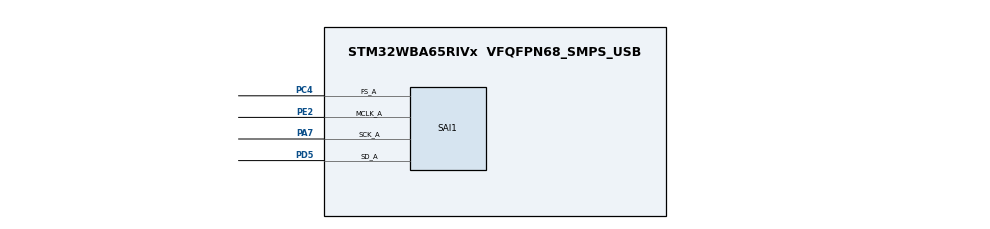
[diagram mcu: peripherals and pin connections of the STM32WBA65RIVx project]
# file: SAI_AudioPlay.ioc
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CORTEX_M33_NS.userName=CORTEX_M33
GPDMA1.LINKEDLISTMODE_GPDMACH7=DMA_LINKEDLIST_CIRCULAR
GPDMA1.PRIORITY_LL_GPDMACH7=DMA_HIGH_PRIORITY
Linkedlist.MDMA_Channel0.GP_SW.0.BlkHWRequest=DMA_BREQ_SINGLE_BURST
Linkedlist.MDMA_Channel0.GP_SW.0.DataHandling=NONE
Linkedlist.MDMA_Channel0.GP_SW.0.DataSize=0
Linkedlist.MDMA_Channel0.GP_SW.0.DestBurstLength=1
Linkedlist.MDMA_Channel0.GP_SW.0.DestDataWidth=DMA_DEST_DATAWIDTH_HALFWORD
Linkedlist.MDMA_Channel0.GP_SW.0.DestInc=DMA_DINC_FIXED
Linkedlist.MDMA_Channel0.GP_SW.0.Direction=DMA_MEMORY_TO_PERIPH
Linkedlist.MDMA_Channel0.GP_SW.0.DstAddress=0
Linkedlist.MDMA_Channel0.GP_SW.0.Instance=MDMA_Channel0
Linkedlist.MDMA_Channel0.GP_SW.0.LL_MASTERDMA=GPDMA1
Linkedlist.MDMA_Channel0.GP_SW.0.LL_NAME=SAIQueue
Linkedlist.MDMA_Channel0.GP_SW.0.LL_TYPE=LINEAR
Linkedlist.MDMA_Channel0.GP_SW.0.NODE_NAME=NodeTx
Linkedlist.MDMA_Channel0.GP_SW.0.Requestforcodegen=GPDMA1_REQUEST_SAI1_A
Linkedlist.MDMA_Channel0.GP_SW.0.SrcAddress=0
Linkedlist.MDMA_Channel0.GP_SW.0.SrcBurstLength=1
Linkedlist.MDMA_Channel0.GP_SW.0.SrcDataWidth=DMA_SRC_DATAWIDTH_HALFWORD
Linkedlist.MDMA_Channel0.GP_SW.0.SrcInc=DMA_SINC_INCREMENTED
Linkedlist.MDMA_Channel0.GP_SW.0.TransferAllocatedPortSrc=DMA_SRC_ALLOCATED_PORT0
Linkedlist.MDMA_Channel0.GP_SW.0.TransferEventMode=DMA_TCEM_BLOCK_TRANSFER
Linkedlist.MDMA_Channel0.GP_SW.0.TriggerPolarity=DMA_TRIG_POLARITY_MASKED
Linkedlist.MDMA_Channel0.Request0=GP_SW
Linkedlist.MDMA_Channel0.RequestsNb=1
Linkedlist.RequestSet0=MDMA_Channel0
Linkedlist.RequestSetsNb=1
Mcu.Family=STM32WBA
Mcu.Name=STM32WBA65RIVx
Mcu.Package=VFQFPN68_SMPS_USB
NVIC.GPDMA1_Channel7_IRQn=true\:0\:0\:false\:false\:true\:true\:true\:true
NVIC.PriorityGroup=NVIC_PRIORITYGROUP_4
OSC_IN.Mode=HSE-External-Oscillator
OSC_IN.PinAttribute=CortexM33
OSC_IN.Signal=RCC_OSC_IN
OSC_OUT.Mode=HSE-External-Oscillator
OSC_OUT.PinAttribute=CortexM33
OSC_OUT.Signal=RCC_OSC_OUT
PA7.Mode=SAI_A_MasterWithClock
PA7.PinAttribute=CortexM33
PA7.Signal=SAI1_SCK_A
PC4.Mode=SAI_A_MasterWithClock
PC4.Signal=SAI1_FS_A
PD5.Mode=SAI_A_MasterWithClock
PD5.Signal=SAI1_SD_A
PE2.Mode=SAI_A_MasterWithClock
PE2.Signal=SAI1_MCLK_A
ProjectManager.HeapSize=0x200
ProjectManager.StackSize=0x400
ProjectManager.TargetToolchain=EWARM V9.20
RCC.ADCFreq_Value=100000000
RCC.AHB5CLKDivider=DIV4
RCC.AHBFreq_Value=100000000
RCC.APB1Freq_Value=100000000
RCC.APB1TimFreq_Value=100000000
RCC.APB2Freq_Value=100000000
RCC.APB2TimFreq_Value=100000000
RCC.CortexFreq_Value=12500000
RCC.HCLKFreq_Value=100000000
RCC.HSE_VALUE=32000000
RCC.HSI_VALUE=16000000
RCC.LSE_VALUE=32768
RCC.LSI1_VALUE=32000
RCC.LSI2_VALUE=32000
RCC.PLLFRACN=4096
RCC.PLLM=2
RCC.PLLN=12
RCC.PLLSourceVirtual=RCC_PLLSOURCE_HSE
RCC.SYSCLKFreq_VALUE=100000000
RCC.SYSCLKSourceVirtual=RCC_SYSCLKSOURCE_PLLCLK
RCC.VCOOutputFreq_Value=200000000
SAI1.ActiveFrameLength-SAI_A_MasterWithClock=16
SAI1.AudioFrequency-SAI_A_MasterWithClock=SAI_AUDIO_FREQUENCY_22K
SAI1.DataSize-SAI_A_MasterWithClock=SAI_DATASIZE_16
SAI1.ErrorAudioFreq-SAI_A_MasterWithClock=41.72 %
SAI1.FIFOThreshold-SAI_A_MasterWithClock=SAI_FIFOTHRESHOLD_1QF
SAI1.FSDefinition-SAI_A_MasterWithClock=SAI_FS_CHANNEL_IDENTIFICATION
SAI1.FSOffset-SAI_A_MasterWithClock=SAI_FS_BEFOREFIRSTBIT
SAI1.FrameLength-SAI_A_MasterWithClock=32
SAI1.Instance-SAI_A_MasterWithClock=SAI$Index_Block_A
SAI1.MckOutput=SAI_MCK_OUTPUT_ENABLE
SAI1.RealAudioFreq-SAI_A_MasterWithClock=31.25 KHz
SAI1.SlotActive-SAI_A_MasterWithClock=0x00000003
SAI1.SlotNumber-SAI_A_MasterWithClock=2
SAI1.VirtualMode-SAI_A_MasterWithClock=VM_MASTER
SAI1.VirtualSlotActive-SAI_A_MasterWithClock=SAI_SLOT_USERSETTING
SAI1.VirtualSlotActive0-SAI_A_MasterWithClock=true
SAI1.VirtualSlotActive1-SAI_A_MasterWithClock=true
VP_CORTEX_M33_NS_VS_Hclk.Mode=Hclk_Mode
VP_GPDMA1_VS_GPDMACH7.Mode=LINKEDLIST_GPDMACH7
VP_ICACHE_VS_ICACHE.Mode=DirectMappedCache
VP_MEMORYMAP_VS_MEMORYMAP.Mode=CurAppReg
VP_PWR_VS_SECSignals.Mode=Security/Privilege
board=custom

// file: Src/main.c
/* USER CODE BEGIN Header */
/**
  ******************************************************************************
  * @file           : main.c
  * @brief          : Main program body
  ******************************************************************************
  * @attention
  *
  * Copyright (c) 2024 STMicroelectronics.
  * All rights reserved.
  *
  * This software is licensed under terms that can be found in the LICENSE file
  * in the root directory of this software component.
  * If no LICENSE file comes with this software, it is provided AS-IS.
  *
  ******************************************************************************
  */
/* USER CODE END Header */
#include "main.h"

/* USER CODE BEGIN Includes */
#include "linked_list.h"
/* USER CODE END Includes */

DMA_HandleTypeDef handle_GPDMA1_Channel7;

SAI_HandleTypeDef hsai_BlockA1;

/* USER CODE BEGIN PV */
static AUDIO_Drv_t *AudioDrv = NULL;
void *AudioCompObj;

/* Buffer location should aligned to cache line size (32 bytes) */
uint16_t PlayBuff[PLAY_BUFF_SIZE];

__IO int16_t UpdatePointer = -1;
WM8904_Init_t codec_init;
 extern DMA_QListTypeDef SAIQueue;
 extern DMA_NodeTypeDef NodeTx;

/* USER CODE END PV */

void SystemClock_Config(void);
static void MX_GPDMA1_Init(void);
static void MX_GPIO_Init(void);
static void MX_ICACHE_Init(void);
static void MX_SAI1_Init(void);
/* USER CODE BEGIN PFP */
static int32_t WM8904_Probe(void);
/* USER CODE END PFP */

int main(void)
{

  /* USER CODE BEGIN 1 */
  /* STM32WBAxx HAL library initialization:
       - Systick timer is configured by default as source of time base, but user
             can eventually implement his proper time base source (a general purpose
             timer for example or other time source), keeping in mind that Time base
             duration should be kept 1ms since PPP_TIMEOUT_VALUEs are defined and
             handled in milliseconds basis.
       - Set NVIC Group Priority to 4
       - Low Level Initialization
     */
  /* USER CODE END 1 */

  /* MCU Configuration--------------------------------------------------------*/

  /* Reset of all peripherals, Initializes the Flash interface and the Systick. */
  HAL_Init();

  /* USER CODE BEGIN Init */
  uint32_t PlaybackPosition   = PLAY_BUFF_SIZE + PLAY_HEADER;
  /* USER CODE END Init */

  /* Configure the system clock */
  SystemClock_Config();

  /* Initialize all configured peripherals */
  MX_GPDMA1_Init();
  MX_GPIO_Init();
  MX_ICACHE_Init();
  MX_SAI1_Init();
  /* USER CODE BEGIN 2 */
  BSP_LED_Init(LD6);
  BSP_LED_Init(LD5);

  /* Check if the buffer has been loaded in flash */
  if(*((uint64_t *)AUDIO_FILE_ADDRESS) != 0x017EFE2446464952 ) Error_Handler();

    /* Associate the DMA handle */
  __HAL_LINKDMA(&hsai_BlockA1, hdmatx, handle_GPDMA1_Channel7);

   MX_SAIQueue_Config();

  /* Set queue circular mode for sai queue */
  HAL_DMAEx_List_SetCircularMode(&SAIQueue);

  /* Link SAI queue to DMA channel */
  HAL_DMAEx_List_LinkQ(&handle_GPDMA1_Channel7, &SAIQueue);

  WM8904_Probe();

 /* Fill codec_init structure */
 codec_init.InputDevice  = WM8904_IN_NONE;
 codec_init.OutputDevice = WM8904_OUT_HEADPHONE;
 codec_init.Frequency    = AUDIO_FREQUENCY_22K;
 codec_init.Resolution   = WM8904_RESOLUTION_16B; /* Not used */
 codec_init.Volume       = 80;

 /* Initialize the codec internal registers */
 if(AudioDrv->Init(AudioCompObj, &codec_init) < 0)
 {
   Error_Handler();
 }

  /* Initialize the data buffer */
  for(int i=0; i < PLAY_BUFF_SIZE; i+=2)
  {
    PlayBuff[i]=*((__IO uint16_t *)(AUDIO_FILE_ADDRESS + PLAY_HEADER + i));
  }

  /* Start the playback */
  if(0 != AudioDrv->Play(AudioCompObj))
  {
    Error_Handler();
  }

  if(HAL_OK != HAL_SAI_Transmit_DMA(&hsai_BlockA1, (uint8_t *)PlayBuff, PLAY_BUFF_SIZE))
  {
    Error_Handler();
  }

  /* USER CODE END 2 */

  /* Infinite loop */
  while (1)
  {

    /* USER CODE BEGIN 3 */
     BSP_LED_Toggle(LD6);

    /* Wait a callback event */
    while(UpdatePointer==-1);

    int position = UpdatePointer;
    UpdatePointer = -1;

    /* Update the first or the second part of the buffer */
    for(int i = 0; i < PLAY_BUFF_SIZE/2; i++)
    {
      PlayBuff[i+position] = *(uint16_t *)(AUDIO_FILE_ADDRESS + PlaybackPosition);
      PlaybackPosition+=2;
    }

    /* check the end of the file */
    if((PlaybackPosition+PLAY_BUFF_SIZE/2) > AUDIO_FILE_SIZE)
    {
      PlaybackPosition = PLAY_HEADER;
    }

    if(UpdatePointer != -1)
    {
      /* Buffer update time is too long compare to the data transfer time */
      Error_Handler();
    }
  }
  /* USER CODE END 3 */
}

void SystemClock_Config(void)
{
  RCC_OscInitTypeDef RCC_OscInitStruct = {0};
  RCC_ClkInitTypeDef RCC_ClkInitStruct = {0};

  /** Supply configuration update enable
  */
  HAL_PWREx_ConfigSupply(PWR_LDO_SUPPLY);

  /** Configure the main internal regulator output voltage
  */
  if (HAL_PWREx_ControlVoltageScaling(PWR_REGULATOR_VOLTAGE_SCALE1) != HAL_OK)
  {
    Error_Handler();
  }

  /** Initializes the CPU, AHB and APB busses clocks
  */
  RCC_OscInitStruct.OscillatorType = RCC_OSCILLATORTYPE_HSI|RCC_OSCILLATORTYPE_HSE;
  RCC_OscInitStruct.HSEState = RCC_HSE_ON;
  RCC_OscInitStruct.HSEDiv = RCC_HSE_DIV1;
  RCC_OscInitStruct.HSIState = RCC_HSI_ON;
  RCC_OscInitStruct.HSICalibrationValue = RCC_HSICALIBRATION_DEFAULT;
  RCC_OscInitStruct.PLL1.PLLState = RCC_PLL_ON;
  RCC_OscInitStruct.PLL1.PLLSource = RCC_PLLSOURCE_HSE;
  RCC_OscInitStruct.PLL1.PLLM = 2;
  RCC_OscInitStruct.PLL1.PLLN = 12;
  RCC_OscInitStruct.PLL1.PLLP = 2;
  RCC_OscInitStruct.PLL1.PLLQ = 2;
  RCC_OscInitStruct.PLL1.PLLR = 2;
  RCC_OscInitStruct.PLL1.PLLFractional = 4096;
  if (HAL_RCC_OscConfig(&RCC_OscInitStruct) != HAL_OK)
  {
    Error_Handler();
  }

  /** Initializes the CPU, AHB and APB busses clocks
  */
  RCC_ClkInitStruct.ClockType = RCC_CLOCKTYPE_HCLK|RCC_CLOCKTYPE_SYSCLK
                              |RCC_CLOCKTYPE_PCLK1|RCC_CLOCKTYPE_PCLK2
                              |RCC_CLOCKTYPE_PCLK7|RCC_CLOCKTYPE_HCLK5;
  RCC_ClkInitStruct.SYSCLKSource = RCC_SYSCLKSOURCE_PLLCLK;
  RCC_ClkInitStruct.AHBCLKDivider = RCC_SYSCLK_DIV1;
  RCC_ClkInitStruct.APB1CLKDivider = RCC_HCLK_DIV1;
  RCC_ClkInitStruct.APB2CLKDivider = RCC_HCLK_DIV1;
  RCC_ClkInitStruct.APB7CLKDivider = RCC_HCLK_DIV1;
  RCC_ClkInitStruct.AHB5_PLL1_CLKDivider = RCC_SYSCLK_PLL1_DIV4;
  RCC_ClkInitStruct.AHB5_HSEHSI_CLKDivider = RCC_SYSCLK_HSEHSI_DIV1;

  if (HAL_RCC_ClockConfig(&RCC_ClkInitStruct, FLASH_LATENCY_3) != HAL_OK)
  {
    Error_Handler();
  }
}

static void MX_GPDMA1_Init(void)
{

  /* Peripheral clock enable */
  __HAL_RCC_GPDMA1_CLK_ENABLE();

  /* GPDMA1 interrupt Init */
    HAL_NVIC_SetPriority(GPDMA1_Channel7_IRQn, 0, 0);
    HAL_NVIC_EnableIRQ(GPDMA1_Channel7_IRQn);

  handle_GPDMA1_Channel7.Instance = GPDMA1_Channel7;
  handle_GPDMA1_Channel7.InitLinkedList.Priority = DMA_HIGH_PRIORITY;
  handle_GPDMA1_Channel7.InitLinkedList.LinkStepMode = DMA_LSM_FULL_EXECUTION;
  handle_GPDMA1_Channel7.InitLinkedList.LinkAllocatedPort = DMA_LINK_ALLOCATED_PORT0;
  handle_GPDMA1_Channel7.InitLinkedList.TransferEventMode = DMA_TCEM_LAST_LL_ITEM_TRANSFER;
  handle_GPDMA1_Channel7.InitLinkedList.LinkedListMode = DMA_LINKEDLIST_CIRCULAR;
  if (HAL_DMAEx_List_Init(&handle_GPDMA1_Channel7) != HAL_OK)
  {
    Error_Handler();
  }
  if (HAL_DMA_ConfigChannelAttributes(&handle_GPDMA1_Channel7, DMA_CHANNEL_NPRIV) != HAL_OK)
  {
    Error_Handler();
  }

}

static void MX_ICACHE_Init(void)
{

  /** Enable instruction cache in 1-way (direct mapped cache)
  */
  if (HAL_ICACHE_ConfigAssociativityMode(ICACHE_1WAY) != HAL_OK)
  {
    Error_Handler();
  }
  if (HAL_ICACHE_Enable() != HAL_OK)
  {
    Error_Handler();
  }

}

static void MX_SAI1_Init(void)
{

  hsai_BlockA1.Instance = SAI1_Block_A;
  hsai_BlockA1.Init.Protocol = SAI_FREE_PROTOCOL;
  hsai_BlockA1.Init.AudioMode = SAI_MODEMASTER_TX;
  hsai_BlockA1.Init.DataSize = SAI_DATASIZE_16;
  hsai_BlockA1.Init.FirstBit = SAI_FIRSTBIT_MSB;
  hsai_BlockA1.Init.ClockStrobing = SAI_CLOCKSTROBING_FALLINGEDGE;
  hsai_BlockA1.Init.Synchro = SAI_ASYNCHRONOUS;
  hsai_BlockA1.Init.OutputDrive = SAI_OUTPUTDRIVE_DISABLE;
  hsai_BlockA1.Init.NoDivider = SAI_MASTERDIVIDER_ENABLE;
  hsai_BlockA1.Init.FIFOThreshold = SAI_FIFOTHRESHOLD_1QF;
  hsai_BlockA1.Init.AudioFrequency = SAI_AUDIO_FREQUENCY_22K;
  hsai_BlockA1.Init.SynchroExt = SAI_SYNCEXT_DISABLE;
  hsai_BlockA1.Init.MckOutput = SAI_MCK_OUTPUT_ENABLE;
  hsai_BlockA1.Init.MonoStereoMode = SAI_STEREOMODE;
  hsai_BlockA1.Init.CompandingMode = SAI_NOCOMPANDING;
  hsai_BlockA1.Init.TriState = SAI_OUTPUT_NOTRELEASED;
  hsai_BlockA1.Init.PdmInit.Activation = DISABLE;
  hsai_BlockA1.Init.PdmInit.MicPairsNbr = 1;
  hsai_BlockA1.Init.PdmInit.ClockEnable = SAI_PDM_CLOCK1_ENABLE;
  hsai_BlockA1.FrameInit.FrameLength = 32;
  hsai_BlockA1.FrameInit.ActiveFrameLength = 16;
  hsai_BlockA1.FrameInit.FSDefinition = SAI_FS_CHANNEL_IDENTIFICATION;
  hsai_BlockA1.FrameInit.FSPolarity = SAI_FS_ACTIVE_LOW;
  hsai_BlockA1.FrameInit.FSOffset = SAI_FS_BEFOREFIRSTBIT;
  hsai_BlockA1.SlotInit.FirstBitOffset = 0;
  hsai_BlockA1.SlotInit.SlotSize = SAI_SLOTSIZE_DATASIZE;
  hsai_BlockA1.SlotInit.SlotNumber = 2;
  hsai_BlockA1.SlotInit.SlotActive = 0x00000003;
  if (HAL_SAI_Init(&hsai_BlockA1) != HAL_OK)
  {
    Error_Handler();
  }

}

static void MX_GPIO_Init(void)
{

  /* GPIO Ports Clock Enable */
  __HAL_RCC_GPIOA_CLK_ENABLE();
  __HAL_RCC_GPIOD_CLK_ENABLE();
  __HAL_RCC_GPIOE_CLK_ENABLE();
  __HAL_RCC_GPIOC_CLK_ENABLE();

}

/* USER CODE BEGIN 4 */
/**
  * @brief  Register Bus IOs if component ID is OK
  * @retval error status
  */
static int32_t WM8904_Probe(void)
{
  int32_t                   ret = BSP_ERROR_NONE;
  WM8904_IO_t               IOCtx;
  static WM8904_Object_t    WM8904Obj;
  uint32_t                  wm8904_id;

  /* Configure the audio driver */
  IOCtx.Address     = AUDIO_I2C_ADDRESS;
  IOCtx.Init        = BSP_I2C1_Init;
  IOCtx.DeInit      = BSP_I2C1_DeInit;
  IOCtx.ReadReg     = BSP_I2C1_ReadReg;
  IOCtx.WriteReg    = BSP_I2C1_WriteReg;
  IOCtx.GetTick     = BSP_GetTick;

  if(WM8904_RegisterBusIO (&WM8904Obj, &IOCtx) != WM8904_OK)
  {
    ret = BSP_ERROR_BUS_FAILURE;
  }
  else if(WM8904_ReadID(&WM8904Obj, &wm8904_id) != WM8904_OK)
  {
    ret = BSP_ERROR_COMPONENT_FAILURE;
  }
  else if((wm8904_id & WM8904_ID_MASK) != WM8904_ID)
  {
    ret = BSP_ERROR_UNKNOWN_COMPONENT;
  }
  else
  {
    AudioDrv = (AUDIO_Drv_t *) &WM8904_Driver;
    AudioCompObj = &WM8904Obj;
  }

  return ret;
}

/**
  * @brief Tx Transfer completed callbacks.
  * @param  hsai : pointer to a SAI_HandleTypeDef structure that contains
  *                the configuration information for SAI module.
  * @retval None
  */
void HAL_SAI_TxCpltCallback(SAI_HandleTypeDef *hsai)
{
  UpdatePointer = PLAY_BUFF_SIZE/2;
}

/**
  * @brief Tx Transfer Half completed callbacks
  * @param  hsai : pointer to a SAI_HandleTypeDef structure that contains
  *                the configuration information for SAI module.
  * @retval None
  */
void HAL_SAI_TxHalfCpltCallback(SAI_HandleTypeDef *hsai)
{
  UpdatePointer = 0;
}

/* USER CODE END 4 */

void Error_Handler(void)
{
  /* USER CODE BEGIN Error_Handler_Debug */
  /* LD5 On in error case */
  BSP_LED_On(LD5);
  __disable_irq();
  while (1)
  {
  }
  /* USER CODE END Error_Handler_Debug */
}
